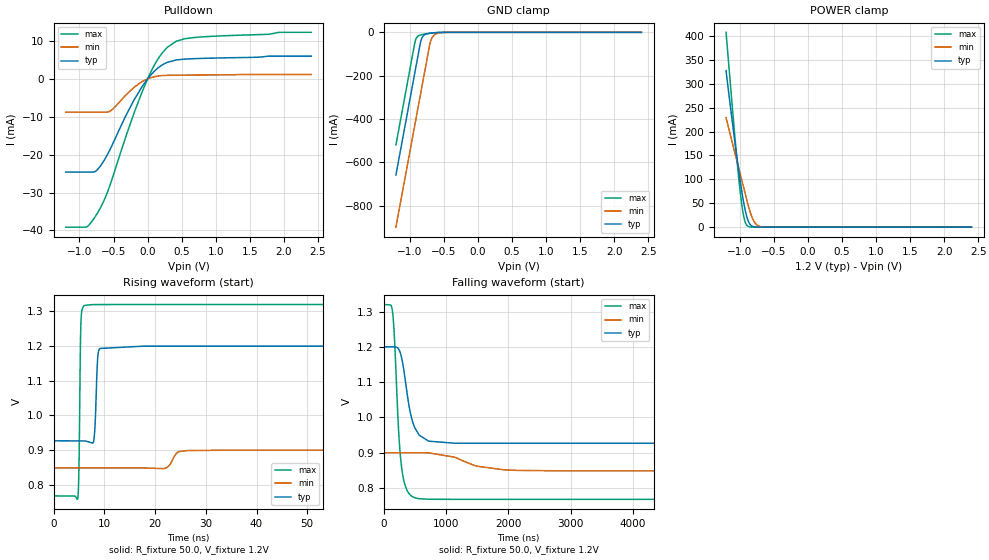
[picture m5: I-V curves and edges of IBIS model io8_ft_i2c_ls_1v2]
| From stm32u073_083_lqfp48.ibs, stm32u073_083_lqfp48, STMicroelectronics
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[Model]   io8_ft_i2c_ls_1v2
Model_type I/O_open_drain
Polarity   Non-Inverting
Enable   Active-Low
| CAP_THRESHOLD on pad IOFT is "UDTCAPC" :
| Rising=30.0% of vddiom   Falling=70.0% of vddiom
| C_comp min and max val. don't necessarily correlate with the min and max pvt
| but are the smallest and greatest pad capacitance found.
| var   typ   min   max
C_comp   2.04020pF  1.89085pF  2.07595pF
|C_comp_pulldown   2.04020pF  1.89085pF  2.07595pF
Vinl = 450.0mV
Vinh = 660.0mV
Vmeas = 600.0mV   | Reference voltage for timing measurements
Cref  = 50.0pF   | Timing specification test load capacitance value
Rref  = 1.0MOhm   | Timing specification test load resistance value
Vref  = 660.0mV   | Timing specification test load voltage
[Model Spec]
| TIME_THRESHOLD on pin ZIV12 is "CMOS" :
| Rising=50.0% of vdd   Falling=50.0% of vdd
Vinl 458.70000mV 361.70000mV 499.70000mV
Vinh 728.30000mV 549.30000mV 792.30000mV
| variable   typ   min   max
[Temperature Range] 25.0 125.0 -40.0
| variable   typ   min   max
[Voltage Range] 1.2V 900.0mV 1.32V
| variable   typ   min   max
[POWER Clamp Reference] 1.2V 900.0mV 1.32V
| variable   typ   min   max
[GND Clamp Reference] 0V 0V 0V
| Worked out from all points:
|   slope of the pulldown table from 0 to 0.18 V, typ, clamps not added: 55.2 ohm
|   GND clamp passes 1 mA (typ) near -0.58 V on its own axis
|   POWER clamp passes 1 mA (typ) near -0.80 V on its own axis
|   rising waveform, R_fixture 50.0, V_fixture 1.2V: 20-80 % time 407ps typ, 1.22ns min, 264ps max; typ from 0.927 V to 1.2 V
|   falling waveform, R_fixture 50.0, V_fixture 1.2V: 20-80 % time 164ns typ, 562ns min, 97.8ns max; typ from 1.2 V to 0.927 V
[POWER Clamp]
-1.2V     327.4mA    228.8mA    407.7mA
-1.07V    177.7mA    155.3mA    188.5mA
-1.03V    134.8mA    132.7mA    126.3mA
-990mV    94.58mA    110.1mA    71.25mA
-960mV    67.13mA    93.17mA    38.08mA
-940mV    50.68mA    81.87mA    21.78mA
-910mV    29.83mA    64.92mA    7.377mA
-880mV    14.86mA    48.18mA    2.007mA
-840mV    4.466mA    28.96mA    309.8uA
-780mV    528.8uA    9.884mA    17.79uA
-670mV    8.746uA    604.9uA    93.25nA
2.4V      0A         0A         0A
[GND Clamp]
-1.2V     -658.2mA   -898.9mA   -519.3mA
-930mV    -199.2mA   -439.9mA   -60.33mA
-910mV    -165.2mA   -405.9mA   -33.58mA
-880mV    -114.2mA   -354.9mA   -18.36mA
-840mV    -46.85mA   -286.9mA   -12.24mA
-820mV    -26.85mA   -252.9mA   -10.71mA
-780mV    -11.1mA    -184.9mA   -8.327mA
-700mV    -4.004mA   -51.26mA   -4.515mA
-670mV    -2.946mA   -24.79mA   -3.345mA
-640mV    -2.117mA   -12.56mA   -2.341mA
-440mV    -36.45uA   -184.8uA   -16.55uA
2.4V      304.1pA    36.47nA    206.9pA
| variable   typ   min   max
[Pullup Reference] 1.2V 900.0mV 1.32V
| variable   typ   min   max
[Pulldown Reference] 0V 0V 0V
[Pulldown]
-1.2V     -24.6mA    -8.807mA   -39.12mA
-890mV    -24.6mA    -8.807mA   -39.02mA
-780mV    -24.54mA   -8.807mA   -36.66mA
-710mV    -23.4mA    -8.807mA   -34.61mA
-530mV    -17.87mA   -8.266mA   -26.91mA
-330mV    -10.09mA   -4.455mA   -15.79mA
-80mV     -2.02mA    -710uA     -3.413mA
110mV     2.211mA    605.8uA    3.97mA
290mV     4.374mA    930.4uA    8.331mA
420mV     4.991mA    971.3uA    9.931mA
670mV     5.322mA    1.008mA    10.89mA
2.4V      6mA        1.156mA    12.28mA
[Ramp]
dV/dt_r 163.89086mV/403.91767ps 30.80776mV/1.21762ns 331.1798mV/261.74897ps
dV/dt_f 163.89639mV/163.50513ns 30.81791mV/469.32648ns 331.18383mV/97.79002ns
R_load = 50.0
| Removed startup time: 0s 0s 0s  .
| Removed end time: 79.75ns.
[Rising Waveform]
R_fixture   = 50.0
V_fixture   = 1.2V
V_fixture_min = 900.0mV
V_fixture_max = 1.32V
0s        926.8mV    848.6mV    768mV
4.8ns     926.6mV    848.6mV    762.8mV
5ns       926.6mV    848.6mV    839.9mV
5.3ns     926.6mV    848.6mV    1.203V
5.4ns     926.6mV    848.6mV    1.268V
6.1ns     926.6mV    848.6mV    1.317V
7.95ns    929.8mV    848.6mV    1.32V
8.7ns     1.165V     848.6mV    1.32V
9.15ns    1.193V     848.6mV    1.32V
79.75ns   1.2V       900mV      1.32V
| Removed startup time: 0s 0s 0s  .
| Removed end time: 6.49975us.
[Falling Waveform]
R_fixture   = 50.0
V_fixture   = 1.2V
V_fixture_min = 900.0mV
V_fixture_max = 1.32V
0s        1.2V       900mV      1.32V
140.3ns   1.2V       900mV      1.302V
172.3ns   1.2V       900mV      1.229V
240.8ns   1.194V     900mV      960.3mV
278.5ns   1.176V     900mV      873.2mV
354.8ns   1.096V     900mV      802.1mV
468.5ns   985.8mV    900mV      775mV
722.3ns   932.8mV    899.7mV    768.2mV
1.146us   927mV      887.2mV    768mV
6.5us     926.8mV    848.6mV    768mV
